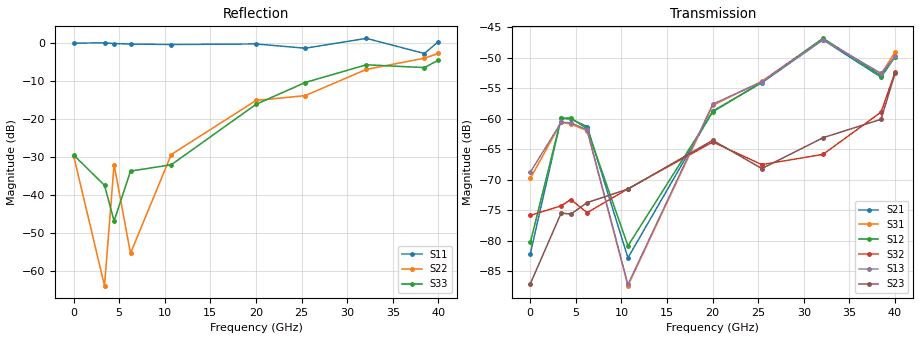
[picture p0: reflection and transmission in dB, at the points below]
! Device:  ADRF5021
! Description: SOI MMIC SPDT Non-Reflective Switch
! Frequency:  9 kHz -  30 GHz
! Ports:
! 	RFC	= Port 1
!	RF1	= Port 2
!	RF2	= Port 3
! Vdd:  +3.3 Volt
! Vss:  -2.5 Volt
! Control:  0/+3.3 Volt
! State:  All Off (Vctl= 0 V, Ven= 3.3 V)
! Data:	Data was collected using a calibrated network analyzer with AFR software.
!	Fixtures were calculated using AFR and fixturing was applied to collect
!	this Deembedded  S Parameter data of ADRF5021.
! Note:	Analog Devices supplies this data as a sample of measured data at the package pin
!	for this product.  Your particular data for this product may vary.
!	Data was taken at 25 degrees C.
!	Analog Devices reserves the right to change this data at anytime.
# Hz S  dB  R 50
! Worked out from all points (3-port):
!   4000 points, 10 MHz to 40 GHz, reference 50 ohm
!   strongest paths, dB at 10 MHz, 10.01 GHz, 20.01 GHz, 30.01 GHz, 40 GHz:
!     S21: -82.1, -76.7, -58.8, -52.5, -49.9
!     S31: -69.8, -78.4, -57.8, -51.8, -49.1
!     S32: -75.8, -72.5, -63.8, -63.6, -52.4
!   lowest |S11| = -2.8 dB at 38.46 GHz (marker M1), VSWR 6.23, Z = 24.1 - j68 ohm
!   |S11| at or under -10 dB: nowhere
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1e7  -0.07 -0.2  -80.27 1.0  -68.77 -66.0
     -82.11 34.4  -29.82 144.2  -87.06 152.1
     -69.80 -15.3  -75.85 -154.1  -29.56 145.2
3.39e9  -0.00 -33.2  -59.96 34.3  -60.62 38.6
        -59.93 33.3  -63.98 -5.7  -75.47 69.7
        -60.60 36.6  -74.30 77.8  -37.55 53.2
4.44e9  -0.19 -42.6  -59.86 26.2  -60.66 31.2
        -60.09 27.4  -32.08 -21.9  -75.66 83.4
        -60.90 30.9  -73.26 82.0  -46.93 -58.0
6.24e9  -0.31 -62.3  -61.69 11.1  -61.86 11.8
        -61.30 9.9  -55.46 -24.4  -73.76 77.6
        -61.98 13.3  -75.41 84.5  -33.79 -39.1
1.071e10  -0.44 -101.5  -80.86 -120.8  -87.17 150.2
          -82.81 -114.0  -29.42 -145.2  -71.55 90.7
          -87.38 163.0  -71.51 90.8  -32.12 -141.8
2.001e10  -0.29 177.9  -58.89 163.5  -57.62 160.1
          -58.76 165.0  -15.17 12.3  -63.55 8.0
          -57.83 159.3  -63.83 8.2  -16.19 6.1
2.539e10  -1.42 101.0  -54.02 125.5  -53.98 127.3
          -54.13 126.1  -13.91 -34.1  -68.19 -58.4
          -53.88 127.6  -67.54 -54.4  -10.45 -41.5
3.21e10  1.18 -3.4  -46.85 88.9  -47.08 75.8
         -47.09 86.5  -6.99 -42.2  -63.13 -50.7
         -46.88 74.7  -65.86 -60.5  -5.78 -70.2
3.846e10  -2.81 -68.3  -53.00 51.8  -52.58 41.2
          -53.21 52.5  -4.05 -54.1  -60.11 -156.3
          -52.74 41.0  -58.94 -156.4  -6.52 -65.4
4e10  0.33 -94.0  -49.84 55.0  -49.81 10.3
      -49.86 57.5  -2.79 -44.4  -52.55 -170.6
      -49.08 10.3  -52.38 -169.9  -4.56 -98.8
